(* Logix 5000 Routine export DNP3Map; software revision 19.01; part 2 of 2 *)

ADD_ON_INSTRUCTION PSDNP3CounterControl16   (* revision 1.0, vendor ProSoft Technology Inc *)
// DNP3 Outstation Counter Control
VAR_IN_OUT
   Control : PSDNP3CounterCtrl; {required}
   Counter : INT; {required}
   FrozenCounter : INT; {required}
END_VAR
VAR_OUTPUT
   CurrentCountValue : DINT; {access Read Only, visible}
   FrozenCountValue : DINT; {access Read Only, visible}
   ClearRequestCount : DINT; {visible}
   FreezeRequestCount : DINT; {access Read Only, visible}
END_VAR
VAR_INPUT
   ResetStatistics : BOOL; {required}
END_VAR
VAR_OUTPUT
   FreezeAction : BOOL; {access Read Only, visible}
   ClearAction : BOOL; {access Read Only, visible}
END_VAR
VAR
   FreezeRequestCounter : COUNTER := (PRE := 2100000000); {access None}
   ClearRequestCounter : COUNTER := (PRE := 2100000000); {access None}
END_VAR

ROUTINE Logic   (* ladder *)
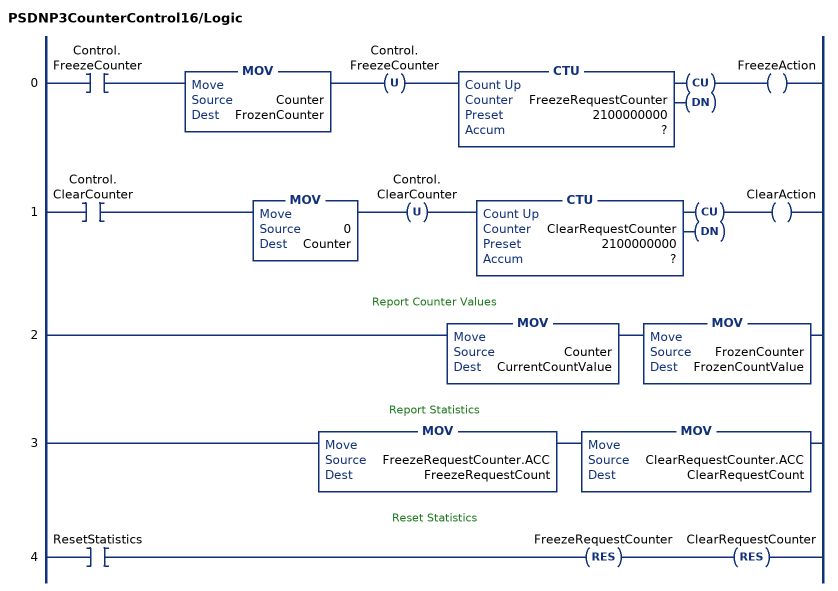
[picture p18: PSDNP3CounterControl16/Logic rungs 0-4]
   0: XIC(Control.FreezeCounter)MOV(Counter,FrozenCounter)OTU(Control.FreezeCounter)CTU(FreezeRequestCounter,?,?)OTE(FreezeAction);
   1: XIC(Control.ClearCounter)MOV(0,Counter)OTU(Control.ClearCounter)CTU(ClearRequestCounter,?,?)OTE(ClearAction);
   // Report Counter Values
   2: MOV(Counter,CurrentCountValue)MOV(FrozenCounter,FrozenCountValue);
   // Report Statistics
   3: MOV(FreezeRequestCounter.ACC,FreezeRequestCount)MOV(ClearRequestCounter.ACC,ClearRequestCount);
   // Reset Statistics
   4: XIC(ResetStatistics)RES(FreezeRequestCounter)RES(ClearRequestCounter);
END_ROUTINE
END_ADD_ON_INSTRUCTION

ADD_ON_INSTRUCTION PSDNP3CounterControl16Flag   (* revision 1.0, vendor ProSoft Technology Inc *)
// DNP3 Outstation Counter Control
VAR_IN_OUT
   Control : PSDNP3CounterCtrl; {required}
   Counter : PSDNP3Counter16WithFlag; {required}
   FrozenCounter : PSDNP3FrozenCounter16WithFlag; {required}
END_VAR
VAR_OUTPUT
   CurrentCountValue : DINT; {access Read Only, visible}
   FrozenCountValue : DINT; {access Read Only, visible}
   ClearRequestCount : DINT; {visible}
   FreezeRequestCount : DINT; {access Read Only, visible}
END_VAR
VAR_INPUT
   ResetStatistics : BOOL; {required}
END_VAR
VAR_OUTPUT
   FreezeAction : BOOL; {access Read Only, visible}
   ClearAction : BOOL; {access Read Only, visible}
END_VAR
VAR
   FreezeRequestCounter : COUNTER := (PRE := 2100000000); {access None}
   ClearRequestCounter : COUNTER := (PRE := 2100000000); {access None}
END_VAR

ROUTINE Logic   (* ladder *)
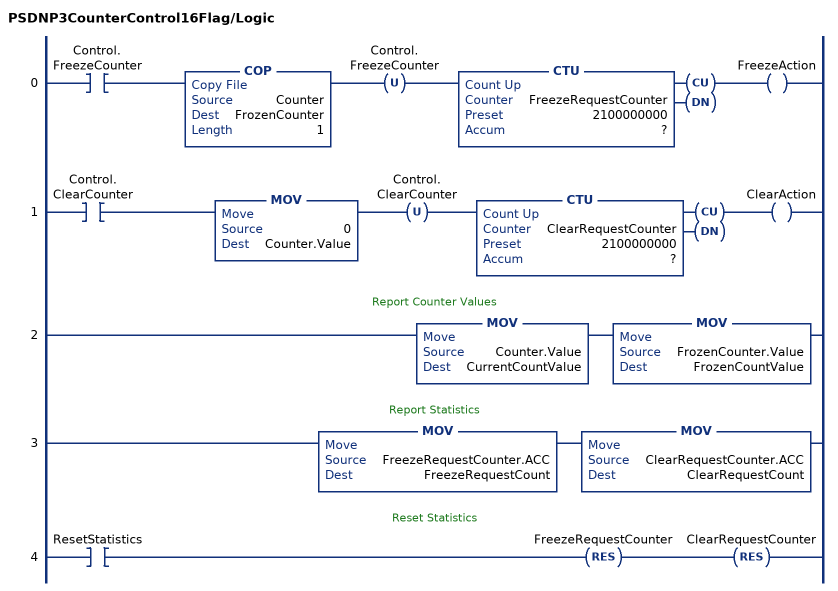
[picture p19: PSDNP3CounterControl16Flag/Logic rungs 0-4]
   0: XIC(Control.FreezeCounter)COP(Counter,FrozenCounter,1)OTU(Control.FreezeCounter)CTU(FreezeRequestCounter,?,?)OTE(FreezeAction);
   1: XIC(Control.ClearCounter)MOV(0,Counter.Value)OTU(Control.ClearCounter)CTU(ClearRequestCounter,?,?)OTE(ClearAction);
   // Report Counter Values
   2: MOV(Counter.Value,CurrentCountValue)MOV(FrozenCounter.Value,FrozenCountValue);
   // Report Statistics
   3: MOV(FreezeRequestCounter.ACC,FreezeRequestCount)MOV(ClearRequestCounter.ACC,ClearRequestCount);
   // Reset Statistics
   4: XIC(ResetStatistics)RES(FreezeRequestCounter)RES(ClearRequestCounter);
END_ROUTINE
END_ADD_ON_INSTRUCTION

ADD_ON_INSTRUCTION PSDNP3CounterControl16FlagTime   (* revision 1.0, vendor ProSoft Technology Inc *)
// DNP3 Outstation Counter Control
VAR_IN_OUT
   Control : PSDNP3CounterCtrl; {required}
   Counter : PSDNP3Counter16WithFlag; {required}
   FrozenCounter : PSDNP3FrozenCounter16WithFlagTimeRev2; {required}
END_VAR
VAR_OUTPUT
   CurrentCountValue : DINT; {access Read Only, visible}
   FrozenCountValue : DINT; {access Read Only, visible}
   ClearRequestCount : DINT; {visible}
   FreezeRequestCount : DINT; {access Read Only, visible}
END_VAR
VAR_INPUT
   ResetStatistics : BOOL; {required}
END_VAR
VAR_OUTPUT
   FreezeAction : BOOL; {access Read Only, visible}
   ClearAction : BOOL; {access Read Only, visible}
END_VAR
VAR
   FreezeRequestCounter : COUNTER := (PRE := 2100000000); {access None}
   ClearRequestCounter : COUNTER := (PRE := 2100000000); {access None}
END_VAR

ROUTINE Logic   (* ladder *)
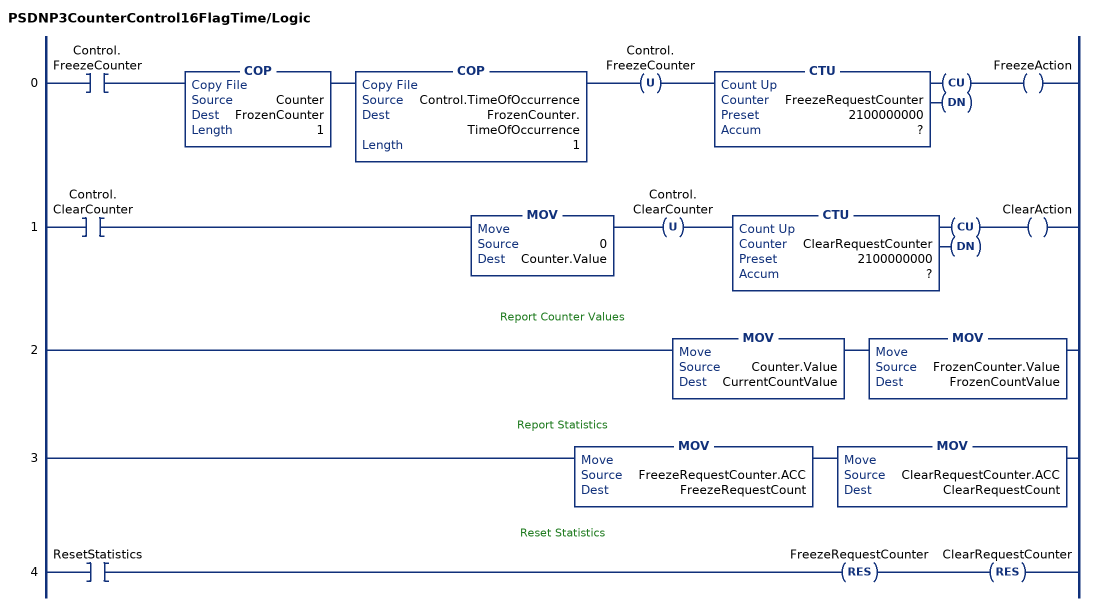
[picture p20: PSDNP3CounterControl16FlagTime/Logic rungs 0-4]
   0: XIC(Control.FreezeCounter)COP(Counter,FrozenCounter,1)COP(Control.TimeOfOccurrence,FrozenCounter.TimeOfOccurrence,1)OTU(Control.FreezeCounter)CTU(FreezeRequestCounter,?,?)OTE(FreezeAction);
   1: XIC(Control.ClearCounter)MOV(0,Counter.Value)OTU(Control.ClearCounter)CTU(ClearRequestCounter,?,?)OTE(ClearAction);
   // Report Counter Values
   2: MOV(Counter.Value,CurrentCountValue)MOV(FrozenCounter.Value,FrozenCountValue);
   // Report Statistics
   3: MOV(FreezeRequestCounter.ACC,FreezeRequestCount)MOV(ClearRequestCounter.ACC,ClearRequestCount);
   // Reset Statistics
   4: XIC(ResetStatistics)RES(FreezeRequestCounter)RES(ClearRequestCounter);
END_ROUTINE
END_ADD_ON_INSTRUCTION

ADD_ON_INSTRUCTION PSDNP3CounterControl32   (* revision 1.0, vendor ProSoft Technology Inc *)
// DNP3 Outstation Counter Control
VAR_IN_OUT
   Control : PSDNP3CounterCtrl; {required}
   Counter : DINT; {required}
   FrozenCounter : DINT; {required}
END_VAR
VAR_OUTPUT
   CurrentCountValue : DINT; {access Read Only, visible}
   FrozenCountValue : DINT; {access Read Only, visible}
   ClearRequestCount : DINT; {visible}
   FreezeRequestCount : DINT; {access Read Only, visible}
END_VAR
VAR_INPUT
   ResetStatistics : BOOL; {required}
END_VAR
VAR_OUTPUT
   FreezeAction : BOOL; {access Read Only, visible}
   ClearAction : BOOL; {access Read Only, visible}
END_VAR
VAR
   FreezeRequestCounter : COUNTER := (PRE := 2100000000); {access None}
   ClearRequestCounter : COUNTER := (PRE := 2100000000); {access None}
END_VAR

ROUTINE Logic   (* ladder *)
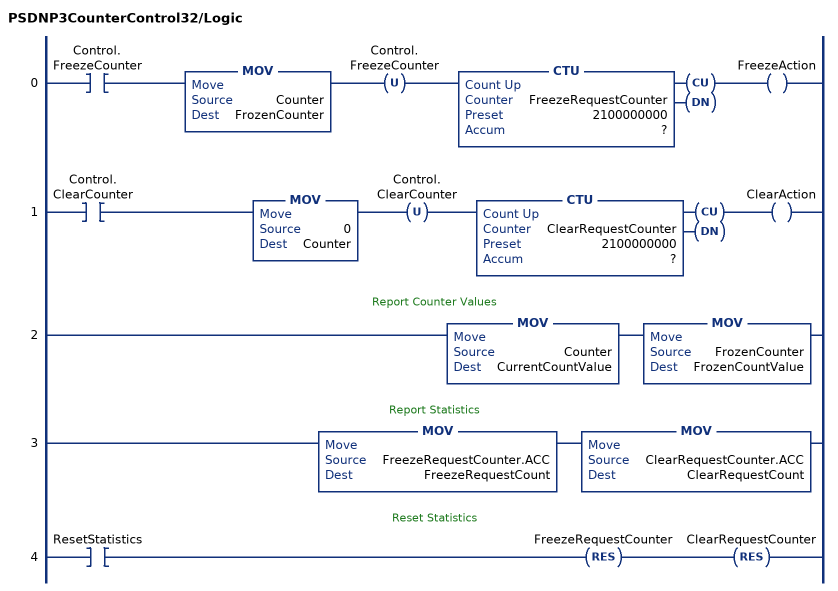
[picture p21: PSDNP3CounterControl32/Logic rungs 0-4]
   0: XIC(Control.FreezeCounter)MOV(Counter,FrozenCounter)OTU(Control.FreezeCounter)CTU(FreezeRequestCounter,?,?)OTE(FreezeAction);
   1: XIC(Control.ClearCounter)MOV(0,Counter)OTU(Control.ClearCounter)CTU(ClearRequestCounter,?,?)OTE(ClearAction);
   // Report Counter Values
   2: MOV(Counter,CurrentCountValue)MOV(FrozenCounter,FrozenCountValue);
   // Report Statistics
   3: MOV(FreezeRequestCounter.ACC,FreezeRequestCount)MOV(ClearRequestCounter.ACC,ClearRequestCount);
   // Reset Statistics
   4: XIC(ResetStatistics)RES(FreezeRequestCounter)RES(ClearRequestCounter);
END_ROUTINE
END_ADD_ON_INSTRUCTION

ADD_ON_INSTRUCTION PSDNP3CounterControl32Flag   (* revision 1.0, vendor ProSoft Technology Inc *)
// DNP3 Outstation Counter Control
VAR_IN_OUT
   Control : PSDNP3CounterCtrl; {required}
   Counter : PSDNP3Counter32WithFlag; {required}
   FrozenCounter : PSDNP3FrozenCounter32WithFlag; {required}
END_VAR
VAR_OUTPUT
   CurrentCountValue : DINT; {access Read Only, visible}
   FrozenCountValue : DINT; {access Read Only, visible}
   ClearRequestCount : DINT; {visible}
   FreezeRequestCount : DINT; {access Read Only, visible}
END_VAR
VAR_INPUT
   ResetStatistics : BOOL; {required}
END_VAR
VAR_OUTPUT
   FreezeAction : BOOL; {access Read Only, visible}
   ClearAction : BOOL; {access Read Only, visible}
END_VAR
VAR
   FreezeRequestCounter : COUNTER := (PRE := 2100000000); {access None}
   ClearRequestCounter : COUNTER := (PRE := 2100000000); {access None}
END_VAR

ROUTINE Logic   (* ladder *)
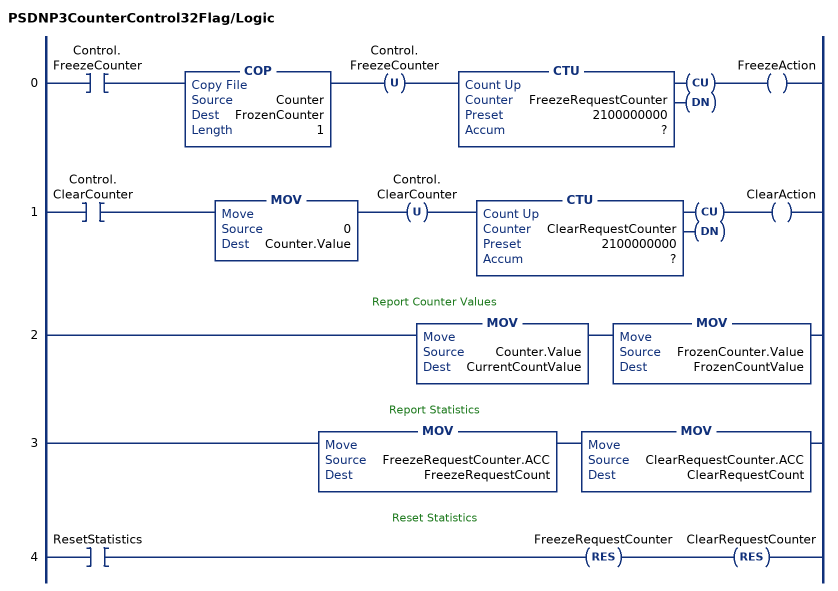
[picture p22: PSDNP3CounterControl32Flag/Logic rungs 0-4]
   0: XIC(Control.FreezeCounter)COP(Counter,FrozenCounter,1)OTU(Control.FreezeCounter)CTU(FreezeRequestCounter,?,?)OTE(FreezeAction);
   1: XIC(Control.ClearCounter)MOV(0,Counter.Value)OTU(Control.ClearCounter)CTU(ClearRequestCounter,?,?)OTE(ClearAction);
   // Report Counter Values
   2: MOV(Counter.Value,CurrentCountValue)MOV(FrozenCounter.Value,FrozenCountValue);
   // Report Statistics
   3: MOV(FreezeRequestCounter.ACC,FreezeRequestCount)MOV(ClearRequestCounter.ACC,ClearRequestCount);
   // Reset Statistics
   4: XIC(ResetStatistics)RES(FreezeRequestCounter)RES(ClearRequestCounter);
END_ROUTINE
END_ADD_ON_INSTRUCTION

ADD_ON_INSTRUCTION PSDNP3CounterControl32FlagTime   (* revision 1.0, vendor ProSoft Technology Inc *)
// DNP3 Outstation Counter Control
VAR_IN_OUT
   Control : PSDNP3CounterCtrl; {required}
   Counter : PSDNP3Counter32WithFlag; {required}
   FrozenCounter : PSDNP3FrozenCounter32WithFlagTime; {required}
END_VAR
VAR_OUTPUT
   CurrentCountValue : DINT; {access Read Only, visible}
   FrozenCountValue : DINT; {access Read Only, visible}
   ClearRequestCount : DINT; {visible}
   FreezeRequestCount : DINT; {access Read Only, visible}
END_VAR
VAR_INPUT
   ResetStatistics : BOOL; {required}
END_VAR
VAR_OUTPUT
   FreezeAction : BOOL; {access Read Only, visible}
   ClearAction : BOOL; {access Read Only, visible}
END_VAR
VAR
   FreezeRequestCounter : COUNTER; {access None}
   ClearRequestCounter : COUNTER; {access None}
END_VAR

ROUTINE Logic   (* ladder *)
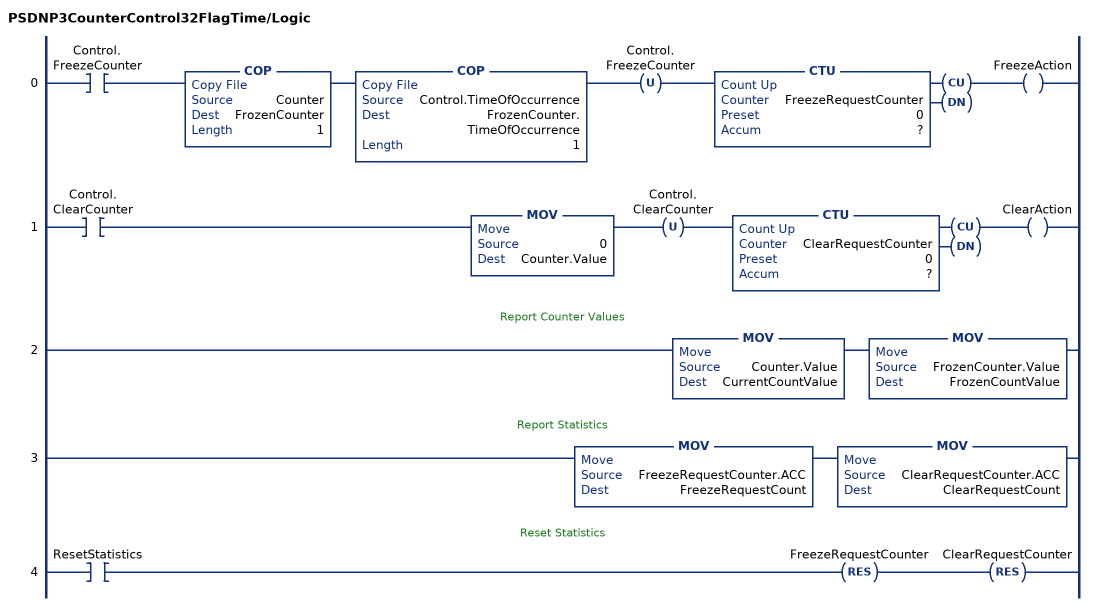
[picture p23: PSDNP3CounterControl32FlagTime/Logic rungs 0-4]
   0: XIC(Control.FreezeCounter)COP(Counter,FrozenCounter,1)COP(Control.TimeOfOccurrence,FrozenCounter.TimeOfOccurrence,1)OTU(Control.FreezeCounter)CTU(FreezeRequestCounter,?,?)OTE(FreezeAction);
   1: XIC(Control.ClearCounter)MOV(0,Counter.Value)OTU(Control.ClearCounter)CTU(ClearRequestCounter,?,?)OTE(ClearAction);
   // Report Counter Values
   2: MOV(Counter.Value,CurrentCountValue)MOV(FrozenCounter.Value,FrozenCountValue);
   // Report Statistics
   3: MOV(FreezeRequestCounter.ACC,FreezeRequestCount)MOV(ClearRequestCounter.ACC,ClearRequestCount);
   // Reset Statistics
   4: XIC(ResetStatistics)RES(FreezeRequestCounter)RES(ClearRequestCounter);
END_ROUTINE
END_ADD_ON_INSTRUCTION

ADD_ON_INSTRUCTION PSDNP3CounterEvtLog16   (* revision 1.0, vendor ProSoft Technology Inc *)
VAR_IN_OUT
   DNP3Object : PSDNP3Counter16WithFlag; {required}
END_VAR
VAR_INPUT
   Deadband : INT; {required}
   MinimumLogInterval : REAL; {required}
   ExtrernalEventTrigger : BOOL; {visible}
END_VAR
VAR_OUTPUT
   EventTriggers : DINT; {access Read Only, visible}
END_VAR
VAR
   RequestLog : BOOL; {access None}
   ExternalONS : BOOL; {access None}
   Interval : TIMER := (PRE := 1000000); {access None}
   PreviousValue : INT; {access None}
   DBRequest : BOOL; {access None}
   ExtRequest : BOOL; {access None}
   Pending : BOOL; {access None}
END_VAR

ROUTINE Logic   (* ladder *)
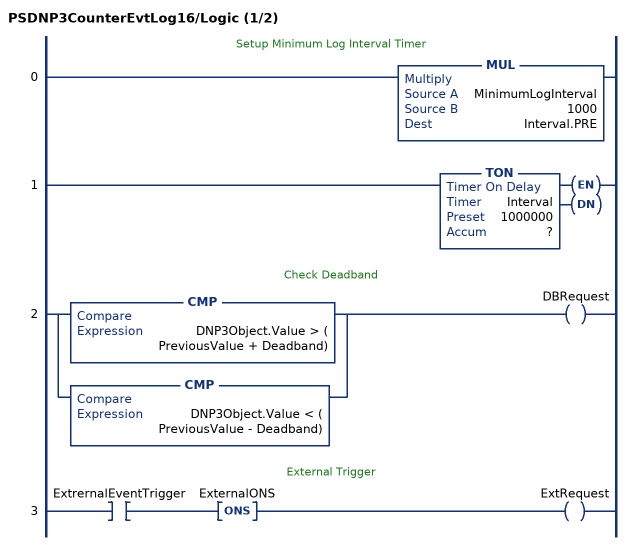
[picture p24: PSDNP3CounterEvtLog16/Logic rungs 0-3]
   // Setup Minimum Log Interval Timer
   0: MUL(MinimumLogInterval,1000,Interval.PRE);
   1: TON(Interval,?,?);
   // Check Deadband
   2: [CMP(DNP3Object.Value > ( PreviousValue + Deadband)) ,CMP(DNP3Object.Value < ( PreviousValue - Deadband)) ]OTE(DBRequest);
   // External Trigger
   3: XIC(ExtrernalEventTrigger)ONS(ExternalONS)OTE(ExtRequest);
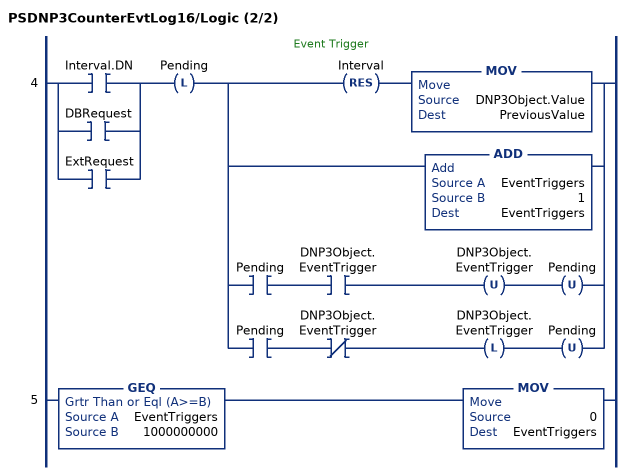
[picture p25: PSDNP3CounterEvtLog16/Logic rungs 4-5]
   // Event Trigger
   4: [XIC(Interval.DN) ,XIC(DBRequest) ,XIC(ExtRequest) ]OTL(Pending)[RES(Interval) MOV(DNP3Object.Value,PreviousValue) ,ADD(EventTriggers,1,EventTriggers) ,XIC(Pending) XIC(DNP3Object.EventTrigger) OTU(DNP3Object.EventTrigger) OTU(Pending) ,XIC(Pending) XIO(DNP3Object.EventTrigger) OTL(DNP3Object.EventTrigger) OTU(Pending) ];
   5: GEQ(EventTriggers,1000000000)MOV(0,EventTriggers);
END_ROUTINE
END_ADD_ON_INSTRUCTION

ADD_ON_INSTRUCTION PSDNP3CounterEvtLog32   (* revision 1.0, vendor ProSoft Technology Inc *)
VAR_IN_OUT
   DNP3Object : PSDNP3Counter32WithFlag; {required}
END_VAR
VAR_INPUT
   Deadband : DINT; {required}
   MinimumLogInterval : REAL; {required}
   ExtrernalEventTrigger : BOOL; {visible}
END_VAR
VAR_OUTPUT
   EventTriggers : DINT; {access Read Only, visible}
END_VAR
VAR
   RequestLog : BOOL; {access None}
   ExternalONS : BOOL; {access None}
   Interval : TIMER := (PRE := 1000000); {access None}
   PreviousValue : DINT; {access None}
   DBRequest : BOOL; {access None}
   ExtRequest : BOOL; {access None}
   Pending : BOOL; {access None}
END_VAR

ROUTINE Logic   (* ladder *)
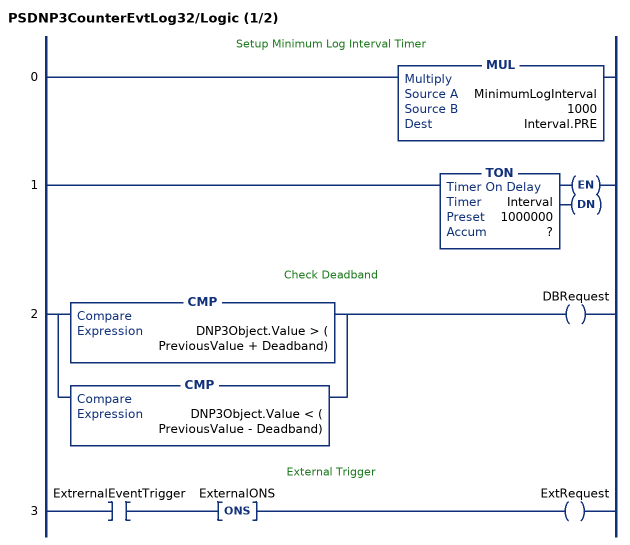
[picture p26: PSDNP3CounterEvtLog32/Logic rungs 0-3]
   // Setup Minimum Log Interval Timer
   0: MUL(MinimumLogInterval,1000,Interval.PRE);
   1: TON(Interval,?,?);
   // Check Deadband
   2: [CMP(DNP3Object.Value > ( PreviousValue + Deadband)) ,CMP(DNP3Object.Value < ( PreviousValue - Deadband)) ]OTE(DBRequest);
   // External Trigger
   3: XIC(ExtrernalEventTrigger)ONS(ExternalONS)OTE(ExtRequest);
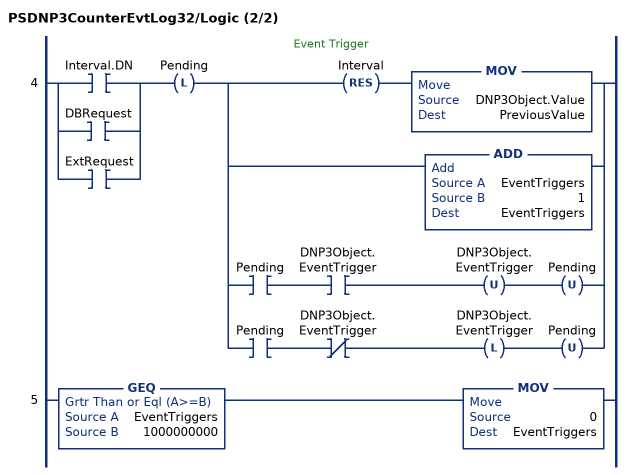
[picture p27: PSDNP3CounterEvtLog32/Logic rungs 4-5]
   // Event Trigger
   4: [XIC(Interval.DN) ,XIC(DBRequest) ,XIC(ExtRequest) ]OTL(Pending)[RES(Interval) MOV(DNP3Object.Value,PreviousValue) ,ADD(EventTriggers,1,EventTriggers) ,XIC(Pending) XIC(DNP3Object.EventTrigger) OTU(DNP3Object.EventTrigger) OTU(Pending) ,XIC(Pending) XIO(DNP3Object.EventTrigger) OTL(DNP3Object.EventTrigger) OTU(Pending) ];
   5: GEQ(EventTriggers,1000000000)MOV(0,EventTriggers);
END_ROUTINE
END_ADD_ON_INSTRUCTION

VAR_GLOBAL   (* controller tags *)
   PLX51DNPSOutput : PLX51DNPOutput;
   PLX51DNPSInput : PLX51DNPInput;
END_VAR

PROGRAM DNP3Outstation

ROUTINE DNP3Map   (* ladder *)
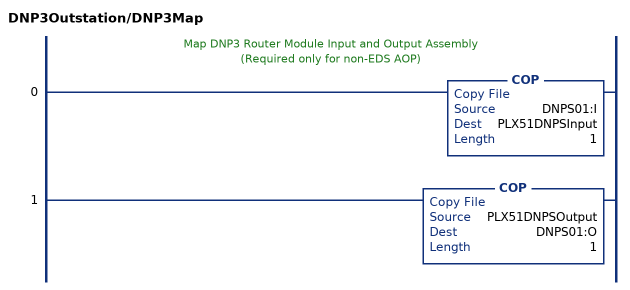
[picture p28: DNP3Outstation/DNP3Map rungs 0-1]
   // Map DNP3 Router Module Input and Output Assembly
   //  (Required only for non-EDS AOP)
   0: COP(DNPS01:I,PLX51DNPSInput,1);
   1: COP(PLX51DNPSOutput,DNPS01:O,1);
END_ROUTINE
END_PROGRAM
